VERSION 5.7 ;
  NOWIREEXTENSIONATPIN ON ;
  DIVIDERCHAR "/" ;
  BUSBITCHARS "[]" ;
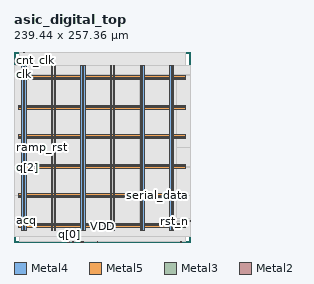
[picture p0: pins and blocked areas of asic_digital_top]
MACRO asic_digital_top
  CLASS BLOCK ;
  FOREIGN asic_digital_top ;
  ORIGIN 0.000 0.000 ;
  SIZE 239.440 BY 257.360 ;
  PIN VDD
    DIRECTION INOUT ;
    USE POWER ;
    PORT
      LAYER Metal4 ;
        RECT 10.720 15.380 12.720 239.420 ;
    END
    PORT
      LAYER Metal4 ;
        RECT 50.720 15.380 52.720 239.420 ;
    END
    PORT
      LAYER Metal4 ;
        RECT 90.720 15.380 92.720 239.420 ;
    END
    PORT
      LAYER Metal4 ;
        RECT 130.720 15.380 132.720 239.420 ;
    END
    PORT
      LAYER Metal4 ;
        RECT 170.720 15.380 172.720 239.420 ;
    END
    PORT
      LAYER Metal4 ;
        RECT 210.720 15.380 212.720 239.420 ;
    END
    PORT
      LAYER Metal5 ;
        RECT 6.720 19.680 232.400 21.680 ;
    END
    PORT
      LAYER Metal5 ;
        RECT 6.720 59.680 232.400 61.680 ;
    END
    PORT
      LAYER Metal5 ;
        RECT 6.720 99.680 232.400 101.680 ;
    END
    PORT
      LAYER Metal5 ;
        RECT 6.720 139.680 232.400 141.680 ;
    END
    PORT
      LAYER Metal5 ;
        RECT 6.720 179.680 232.400 181.680 ;
    END
    PORT
      LAYER Metal5 ;
        RECT 6.720 219.680 232.400 221.680 ;
    END
  END VDD
  PIN VSS
    DIRECTION INOUT ;
    USE GROUND ;
    PORT
      LAYER Metal4 ;
        RECT 14.420 15.380 16.420 239.420 ;
    END
    PORT
      LAYER Metal4 ;
        RECT 54.420 15.380 56.420 239.420 ;
    END
    PORT
      LAYER Metal4 ;
        RECT 94.420 15.380 96.420 239.420 ;
    END
    PORT
      LAYER Metal4 ;
        RECT 134.420 15.380 136.420 239.420 ;
    END
    PORT
      LAYER Metal4 ;
        RECT 174.420 15.380 176.420 239.420 ;
    END
    PORT
      LAYER Metal4 ;
        RECT 214.420 15.380 216.420 239.420 ;
    END
    PORT
      LAYER Metal5 ;
        RECT 6.720 23.380 232.400 25.380 ;
    END
    PORT
      LAYER Metal5 ;
        RECT 6.720 63.380 232.400 65.380 ;
    END
    PORT
      LAYER Metal5 ;
        RECT 6.720 103.380 232.400 105.380 ;
    END
    PORT
      LAYER Metal5 ;
        RECT 6.720 143.380 232.400 145.380 ;
    END
    PORT
      LAYER Metal5 ;
        RECT 6.720 183.380 232.400 185.380 ;
    END
    PORT
      LAYER Metal5 ;
        RECT 6.720 223.380 232.400 225.380 ;
    END
  END VSS
  PIN acq
    DIRECTION OUTPUT ;
    USE SIGNAL ;
    ANTENNADIFFAREA 1.237600 ;
    PORT
      LAYER Metal3 ;
        RECT 0.000 29.120 0.560 29.680 ;
    END
  END acq
  PIN clk
    DIRECTION INPUT ;
    USE SIGNAL ;
    ANTENNAGATEAREA 4.704000 ;
    PORT
      LAYER Metal3 ;
        RECT 0.000 226.240 0.560 226.800 ;
    END
  END clk
  PIN cnt_clk
    DIRECTION OUTPUT ;
    USE SIGNAL ;
    ANTENNADIFFAREA 1.237600 ;
    PORT
      LAYER Metal2 ;
        RECT 13.440 256.800 14.000 257.360 ;
    END
  END cnt_clk
  PIN conversion_busy
    DIRECTION OUTPUT ;
    USE SIGNAL ;
    ANTENNADIFFAREA 1.237600 ;
    PORT
      LAYER Metal3 ;
        RECT 0.000 30.240 0.560 30.800 ;
    END
  END conversion_busy
  PIN conversion_done
    DIRECTION OUTPUT ;
    USE SIGNAL ;
    ANTENNADIFFAREA 1.237600 ;
    PORT
      LAYER Metal2 ;
        RECT 113.120 0.000 113.680 0.560 ;
    END
  END conversion_done
  PIN conversion_timeout[0]
    DIRECTION OUTPUT ;
    USE SIGNAL ;
    ANTENNADIFFAREA 1.237600 ;
    PORT
      LAYER Metal2 ;
        RECT 79.520 0.000 80.080 0.560 ;
    END
  END conversion_timeout[0]
  PIN conversion_timeout[1]
    DIRECTION OUTPUT ;
    USE SIGNAL ;
    ANTENNADIFFAREA 1.237600 ;
    PORT
      LAYER Metal2 ;
        RECT 94.080 0.000 94.640 0.560 ;
    END
  END conversion_timeout[1]
  PIN conversion_timeout[2]
    DIRECTION OUTPUT ;
    USE SIGNAL ;
    ANTENNADIFFAREA 1.237600 ;
    PORT
      LAYER Metal2 ;
        RECT 90.720 0.000 91.280 0.560 ;
    END
  END conversion_timeout[2]
  PIN conversion_timeout[3]
    DIRECTION OUTPUT ;
    USE SIGNAL ;
    ANTENNADIFFAREA 1.237600 ;
    PORT
      LAYER Metal2 ;
        RECT 91.840 0.000 92.400 0.560 ;
    END
  END conversion_timeout[3]
  PIN data_ready
    DIRECTION OUTPUT ;
    USE SIGNAL ;
    ANTENNADIFFAREA 1.237600 ;
    PORT
      LAYER Metal2 ;
        RECT 226.240 0.000 226.800 0.560 ;
    END
  END data_ready
  PIN q[0]
    DIRECTION INPUT ;
    USE SIGNAL ;
    ANTENNAGATEAREA 0.666400 ;
    PORT
      LAYER Metal2 ;
        RECT 75.040 0.000 75.600 0.560 ;
    END
  END q[0]
  PIN q[1]
    DIRECTION INPUT ;
    USE SIGNAL ;
    ANTENNAGATEAREA 0.666400 ;
    PORT
      LAYER Metal2 ;
        RECT 72.800 0.000 73.360 0.560 ;
    END
  END q[1]
  PIN q[2]
    DIRECTION INPUT ;
    USE SIGNAL ;
    ANTENNAGATEAREA 0.666400 ;
    PORT
      LAYER Metal3 ;
        RECT 0.000 100.800 0.560 101.360 ;
    END
  END q[2]
  PIN q[3]
    DIRECTION INPUT ;
    USE SIGNAL ;
    ANTENNAGATEAREA 0.666400 ;
    PORT
      LAYER Metal2 ;
        RECT 73.920 0.000 74.480 0.560 ;
    END
  END q[3]
  PIN ramp_rst
    DIRECTION OUTPUT ;
    USE SIGNAL ;
    ANTENNADIFFAREA 1.237600 ;
    PORT
      LAYER Metal3 ;
        RECT 0.000 127.680 0.560 128.240 ;
    END
  END ramp_rst
  PIN rst_n
    DIRECTION INPUT ;
    USE SIGNAL ;
    ANTENNAGATEAREA 1.999200 ;
    PORT
      LAYER Metal3 ;
        RECT 238.880 28.000 239.440 28.560 ;
    END
  END rst_n
  PIN serial_data
    DIRECTION OUTPUT ;
    USE SIGNAL ;
    ANTENNADIFFAREA 1.237600 ;
    PORT
      LAYER Metal3 ;
        RECT 238.880 62.720 239.440 63.280 ;
    END
  END serial_data
  PIN shift_en
    DIRECTION INPUT ;
    USE SIGNAL ;
    ANTENNAGATEAREA 0.666400 ;
    PORT
      LAYER Metal2 ;
        RECT 225.120 0.000 225.680 0.560 ;
    END
  END shift_en
  PIN start
    DIRECTION INPUT ;
    USE SIGNAL ;
    ANTENNAGATEAREA 0.666400 ;
    PORT
      LAYER Metal3 ;
        RECT 0.000 31.360 0.560 31.920 ;
    END
  END start
  OBS
      LAYER Nwell ;
        RECT 6.290 15.250 232.830 239.550 ;
      LAYER Metal1 ;
        RECT 6.720 15.380 232.400 239.420 ;
      LAYER Metal2 ;
        RECT 7.980 256.500 13.140 256.800 ;
        RECT 14.300 256.500 231.700 256.800 ;
        RECT 7.980 0.860 231.700 256.500 ;
        RECT 7.980 0.140 72.500 0.860 ;
        RECT 75.900 0.140 79.220 0.860 ;
        RECT 80.380 0.140 90.420 0.860 ;
        RECT 92.700 0.140 93.780 0.860 ;
        RECT 94.940 0.140 112.820 0.860 ;
        RECT 113.980 0.140 224.820 0.860 ;
        RECT 227.100 0.140 231.700 0.860 ;
      LAYER Metal3 ;
        RECT 0.560 227.100 238.880 239.260 ;
        RECT 0.860 225.940 238.880 227.100 ;
        RECT 0.560 128.540 238.880 225.940 ;
        RECT 0.860 127.380 238.880 128.540 ;
        RECT 0.560 101.660 238.880 127.380 ;
        RECT 0.860 100.500 238.880 101.660 ;
        RECT 0.560 63.580 238.880 100.500 ;
        RECT 0.560 62.420 238.580 63.580 ;
        RECT 0.560 32.220 238.880 62.420 ;
        RECT 0.860 28.860 238.880 32.220 ;
        RECT 0.860 28.820 238.580 28.860 ;
        RECT 0.560 27.700 238.580 28.820 ;
        RECT 0.560 7.980 238.880 27.700 ;
      LAYER Metal4 ;
        RECT 9.660 21.370 10.420 226.710 ;
        RECT 13.020 21.370 14.120 226.710 ;
        RECT 16.720 21.370 50.420 226.710 ;
        RECT 53.020 21.370 54.120 226.710 ;
        RECT 56.720 21.370 90.420 226.710 ;
        RECT 93.020 21.370 94.120 226.710 ;
        RECT 96.720 21.370 130.420 226.710 ;
        RECT 133.020 21.370 134.120 226.710 ;
        RECT 136.720 21.370 170.420 226.710 ;
        RECT 173.020 21.370 174.120 226.710 ;
        RECT 176.720 21.370 210.420 226.710 ;
        RECT 213.020 21.370 214.120 226.710 ;
        RECT 216.720 21.370 219.940 226.710 ;
  END
END asic_digital_top
END LIBRARY

